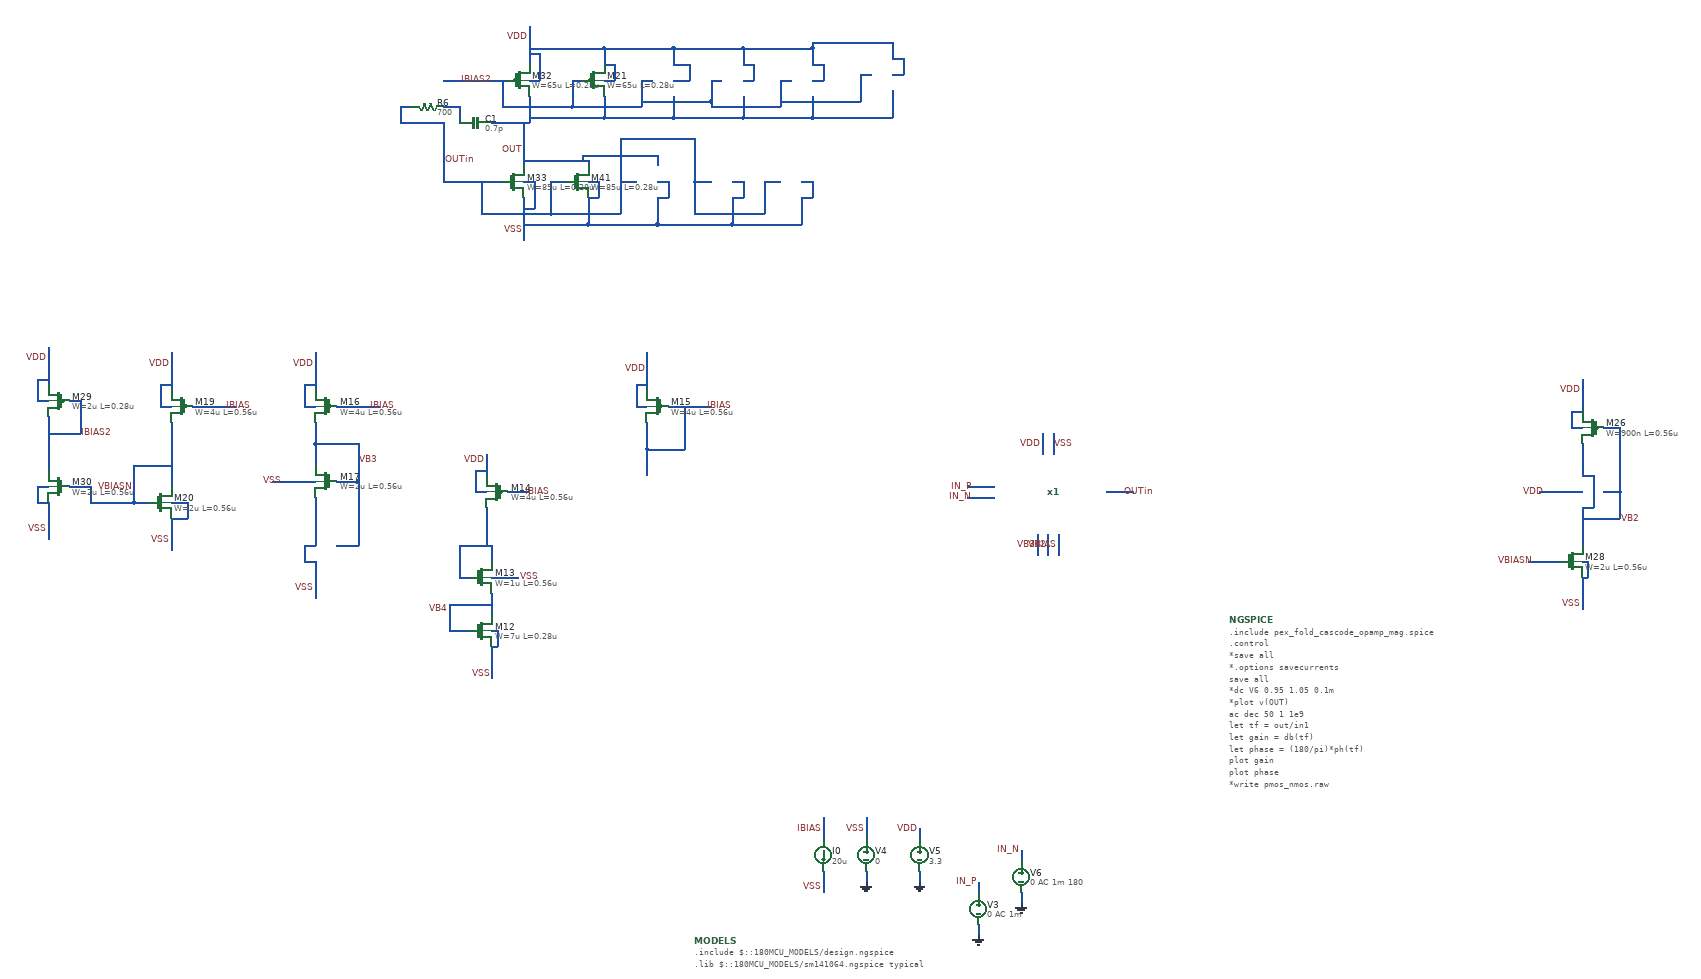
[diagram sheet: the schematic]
v {xschem version=3.1.0 file_version=1.2
}
G {}
K {}
V {}
S {}
E {}
N -460 300 -460 320 {
lab=GND}
N -460 220 -460 240 {
lab=IN_N}
N -670 200 -670 220 {
lab=GND}
N -570 200 -570 220 {
lab=GND}
N -570 120 -570 140 {
lab=VDD}
N -670 100 -670 140 {
lab=VSS}
N -380 240 -380 260 {
lab=GND}
N -380 160 -380 180 {
lab=IN_N}
N -750 200 -750 240 {
lab=VSS}
N -750 100 -750 140 {
lab=IBIAS}
N -1080 -770 -1080 -700 {
lab=VDD}
N -1100 -670 -1080 -670 {
lab=VDD}
N -1100 -710 -1100 -670 {
lab=VDD}
N -1100 -710 -1080 -710 {
lab=VDD}
N -1040 -670 -960 -670 {
lab=IBIAS}
N -1080 -640 -1080 -590 {
lab=IBIAS}
N -1080 -590 -1010 -590 {
lab=IBIAS}
N -1010 -670 -1010 -590 {
lab=IBIAS}
N -1080 -590 -1080 -540 {
lab=IBIAS}
N -1700 -770 -1700 -700 {
lab=VDD}
N -1720 -670 -1700 -670 {
lab=VDD}
N -1720 -710 -1720 -670 {
lab=VDD}
N -1720 -710 -1700 -710 {
lab=VDD}
N -1660 -670 -1580 -670 {
lab=IBIAS}
N -1700 -380 -1700 -310 {
lab=VSS}
N -1660 -410 -1620 -410 {
lab=VB3}
N -1620 -460 -1620 -410 {
lab=VB3}
N -1700 -460 -1700 -440 {
lab=VSS}
N -1700 -500 -1700 -460 {
lab=VSS}
N -1660 -530 -1620 -530 {
lab=VB3}
N -1620 -530 -1620 -460 {
lab=VB3}
N -1620 -600 -1620 -530 {
lab=VB3}
N -1700 -600 -1620 -600 {
lab=VB3}
N -1700 -640 -1700 -600 {
lab=VB3}
N -1700 -600 -1700 -560 {
lab=VB3}
N -1780 -530 -1700 -530 {
lab=VSS}
N -1720 -410 -1720 -380 {
lab=VSS}
N -1720 -380 -1700 -380 {
lab=VSS}
N -1970 -770 -1970 -700 {
lab=VDD}
N -1990 -670 -1970 -670 {
lab=VDD}
N -1990 -710 -1990 -670 {
lab=VDD}
N -1990 -710 -1970 -710 {
lab=VDD}
N -1930 -670 -1850 -670 {
lab=IBIAS}
N -1970 -640 -1970 -520 {
lab=VBIASN}
N -1970 -460 -1970 -400 {
lab=VSS}
N -1970 -490 -1940 -490 {
lab=VSS}
N -1940 -490 -1940 -460 {
lab=VSS}
N -1970 -460 -1940 -460 {
lab=VSS}
N -2040 -490 -2010 -490 {
lab=VBIASN}
N -2040 -560 -2040 -490 {
lab=VBIASN}
N -2040 -560 -1970 -560 {
lab=VBIASN}
N 670 -480 670 -410 {
lab=VB2}
N 670 -380 680 -380 {
lab=VSS}
N 680 -380 680 -350 {
lab=VSS}
N 670 -350 680 -350 {
lab=VSS}
N 670 -350 670 -290 {
lab=VSS}
N 570 -380 630 -380 {
lab=VBIASN}
N 650 -510 670 -510 {
lab=VDD}
N 670 -600 670 -540 {
lab=VB2}
N 590 -510 650 -510 {
lab=VDD}
N 670 -720 670 -660 {
lab=VDD}
N 710 -630 740 -630 {
lab=VB2}
N 670 -460 740 -460 {
lab=VB2}
N 710 -510 740 -510 {
lab=VB2}
N 650 -630 670 -630 {
lab=VDD}
N 650 -660 650 -630 {
lab=VDD}
N 650 -660 670 -660 {
lab=VDD}
N -2200 -780 -2200 -710 {
lab=VDD}
N -2220 -680 -2200 -680 {
lab=VDD}
N -2220 -720 -2220 -680 {
lab=VDD}
N -2220 -720 -2200 -720 {
lab=VDD}
N -2200 -490 -2200 -420 {
lab=VSS}
N -2220 -520 -2200 -520 {
lab=VSS}
N -2220 -520 -2220 -490 {
lab=VSS}
N -2220 -490 -2200 -490 {
lab=VSS}
N -2160 -520 -2120 -520 {
lab=VBIASN}
N -2120 -520 -2120 -490 {
lab=VBIASN}
N -2120 -490 -2040 -490 {
lab=VBIASN}
N -2200 -650 -2200 -550 {
lab=IBIAS2}
N -2160 -680 -2140 -680 {
lab=IBIAS2}
N -2140 -680 -2140 -620 {
lab=IBIAS2}
N -2200 -620 -2140 -620 {
lab=IBIAS2}
N -1300 -1380 -1300 -1310 {
lab=VDD}
N -1300 -1280 -1280 -1280 {
lab=VDD}
N -1280 -1330 -1280 -1280 {
lab=VDD}
N -1300 -1330 -1280 -1330 {
lab=VDD}
N -1460 -1280 -1340 -1280 {
lab=IBIAS2}
N -1370 -1200 -1300 -1200 {
lab=OUT}
N -1300 -1250 -1300 -1200 {
lab=OUT}
N -1310 -1200 -1310 -1120 {
lab=OUT}
N -1310 -1060 -1310 -980 {
lab=VSS}
N -1310 -1090 -1290 -1090 {
lab=VSS}
N -1290 -1090 -1290 -1040 {
lab=VSS}
N -1310 -1040 -1290 -1040 {
lab=VSS}
N -1460 -1200 -1460 -1090 {
lab=OUTin}
N -1460 -1090 -1350 -1090 {
lab=OUTin}
N -1220 -1280 -1200 -1280 {
lab=IBIAS2}
N -1220 -1280 -1220 -1230 {
lab=IBIAS2}
N -1330 -1230 -1220 -1230 {
lab=IBIAS2}
N -1350 -1230 -1330 -1230 {
lab=IBIAS2}
N -1350 -1280 -1350 -1230 {
lab=IBIAS2}
N -1160 -1340 -1160 -1310 {
lab=VDD}
N -1300 -1340 -1160 -1340 {
lab=VDD}
N -1160 -1280 -1140 -1280 {
lab=VDD}
N -1140 -1310 -1140 -1280 {
lab=VDD}
N -1160 -1310 -1140 -1310 {
lab=VDD}
N -1160 -1250 -1160 -1210 {
lab=OUT}
N -1300 -1210 -1160 -1210 {
lab=OUT}
N -1540 -1230 -1520 -1230 {
lab=OUTin}
N -1540 -1230 -1540 -1200 {
lab=OUTin}
N -1540 -1200 -1460 -1200 {
lab=OUTin}
N -1430 -1230 -1430 -1200 {
lab=#net1}
N -1460 -1230 -1430 -1230 {
lab=#net1}
N -1030 -1340 -1030 -1310 {
lab=VDD}
N -1160 -1340 -1030 -1340 {
lab=VDD}
N -1030 -1250 -1030 -1210 {
lab=OUT}
N -1160 -1210 -1030 -1210 {
lab=OUT}
N -1090 -1280 -1070 -1280 {
lab=IBIAS2}
N -1090 -1280 -1090 -1230 {
lab=IBIAS2}
N -1220 -1230 -1090 -1230 {
lab=IBIAS2}
N -1030 -1280 -1000 -1280 {
lab=VDD}
N -1000 -1310 -1000 -1280 {
lab=VDD}
N -1030 -1310 -1000 -1310 {
lab=VDD}
N -1260 -1090 -1230 -1090 {
lab=OUTin}
N -1260 -1090 -1260 -1030 {
lab=OUTin}
N -1390 -1030 -1260 -1030 {
lab=OUTin}
N -1390 -1090 -1390 -1030 {
lab=OUTin}
N -1190 -1130 -1190 -1120 {
lab=OUT}
N -1310 -1130 -1190 -1130 {
lab=OUT}
N -1190 -1060 -1190 -1010 {
lab=VSS}
N -1310 -1010 -1190 -1010 {
lab=VSS}
N -1190 -1090 -1170 -1090 {
lab=VSS}
N -1170 -1090 -1170 -1060 {
lab=VSS}
N -1190 -1060 -1170 -1060 {
lab=VSS}
N -900 -1340 -900 -1310 {
lab=VDD}
N -1030 -1340 -900 -1340 {
lab=VDD}
N -900 -1280 -880 -1280 {
lab=VDD}
N -880 -1310 -880 -1280 {
lab=VDD}
N -900 -1310 -880 -1310 {
lab=VDD}
N -960 -1280 -940 -1280 {
lab=IBIAS2}
N -960 -1280 -960 -1240 {
lab=IBIAS2}
N -1090 -1240 -960 -1240 {
lab=IBIAS2}
N -900 -1250 -900 -1210 {
lab=OUT}
N -1030 -1210 -900 -1210 {
lab=OUT}
N -1060 -1140 -1060 -1120 {
lab=OUT}
N -1200 -1140 -1060 -1140 {
lab=OUT}
N -1200 -1140 -1200 -1130 {
lab=OUT}
N -1130 -1090 -1100 -1090 {
lab=OUTin}
N -1130 -1090 -1130 -1030 {
lab=OUTin}
N -1260 -1030 -1130 -1030 {
lab=OUTin}
N -1190 -1010 -1060 -1010 {
lab=VSS}
N -1060 -1060 -1060 -1010 {
lab=VSS}
N -1060 -1090 -1040 -1090 {
lab=VSS}
N -1040 -1090 -1040 -1060 {
lab=VSS}
N -1060 -1060 -1040 -1060 {
lab=VSS}
N -770 -1340 -770 -1310 {
lab=VDD}
N -900 -1340 -770 -1340 {
lab=VDD}
N -900 -1210 -770 -1210 {
lab=OUT}
N -770 -1250 -770 -1210 {
lab=OUT}
N -770 -1280 -750 -1280 {
lab=VDD}
N -750 -1310 -750 -1280 {
lab=VDD}
N -770 -1310 -750 -1310 {
lab=VDD}
N -830 -1280 -810 -1280 {
lab=IBIAS2}
N -830 -1280 -830 -1230 {
lab=IBIAS2}
N -960 -1230 -830 -1230 {
lab=IBIAS2}
N -960 -1240 -960 -1230 {
lab=IBIAS2}
N -990 -1090 -960 -1090 {
lab=OUTin}
N -990 -1090 -990 -1030 {
lab=OUTin}
N -920 -1060 -920 -1010 {
lab=VSS}
N -920 -1090 -900 -1090 {
lab=VSS}
N -900 -1090 -900 -1060 {
lab=VSS}
N -920 -1060 -900 -1060 {
lab=VSS}
N -860 -1090 -830 -1090 {
lab=OUTin}
N -860 -1090 -860 -1030 {
lab=OUTin}
N -990 -1030 -860 -1030 {
lab=OUTin}
N -920 -1010 -790 -1010 {
lab=VSS}
N -790 -1060 -790 -1010 {
lab=VSS}
N -790 -1090 -770 -1090 {
lab=VSS}
N -770 -1090 -770 -1060 {
lab=VSS}
N -790 -1060 -770 -1060 {
lab=VSS}
N -1060 -1010 -920 -1010 {
lab=VSS}
N -990 -1170 -990 -1090 {
lab=OUTin}
N -1130 -1170 -990 -1170 {
lab=OUTin}
N -1130 -1170 -1130 -1080 {
lab=OUTin}
N -620 -1350 -620 -1320 {
lab=VDD}
N -620 -1260 -620 -1220 {
lab=OUT}
N -620 -1290 -600 -1290 {
lab=VDD}
N -600 -1320 -600 -1290 {
lab=VDD}
N -620 -1320 -600 -1320 {
lab=VDD}
N -680 -1290 -660 -1290 {
lab=IBIAS2}
N -680 -1290 -680 -1240 {
lab=IBIAS2}
N -770 -1350 -620 -1350 {
lab=VDD}
N -770 -1350 -770 -1340 {
lab=VDD}
N -620 -1220 -620 -1210 {
lab=OUT}
N -770 -1210 -620 -1210 {
lab=OUT}
N -830 -1240 -680 -1240 {
lab=IBIAS2}
N -1370 -250 -1360 -250 {
lab=VSS}
N -1360 -250 -1360 -220 {
lab=VSS}
N -1370 -220 -1360 -220 {
lab=VSS}
N -1370 -220 -1370 -160 {
lab=VSS}
N -1370 -350 -1320 -350 {
lab=VSS}
N -1370 -320 -1370 -280 {
lab=VB4}
N -1430 -350 -1410 -350 {
lab=#net2}
N -1430 -410 -1430 -350 {
lab=#net2}
N -1430 -410 -1370 -410 {
lab=#net2}
N -1370 -410 -1370 -380 {
lab=#net2}
N -1380 -480 -1380 -410 {
lab=#net2}
N -1380 -580 -1380 -540 {
lab=VDD}
N -1400 -510 -1380 -510 {
lab=VDD}
N -1400 -550 -1400 -510 {
lab=VDD}
N -1400 -550 -1380 -550 {
lab=VDD}
N -1340 -510 -1300 -510 {
lab=IBIAS}
N -1450 -300 -1370 -300 {
lab=VB4}
N -1450 -300 -1450 -250 {
lab=VB4}
N -1450 -250 -1410 -250 {
lab=VB4}
N 740 -630 740 -570 {
lab=VB2}
N 740 -510 740 -460 {
lab=VB2}
N 740 -570 740 -510 {
lab=VB2}
N 670 -480 690 -480 {
lab=VB2}
N 690 -540 690 -480 {
lab=VB2}
N 670 -540 690 -540 {
lab=VB2}
N -1720 -410 -1700 -410 {
lab=VSS}
N -1700 -440 -1700 -410 {
lab=VSS}
N -340 -620 -340 -580 {
lab=VDD}
N -320 -620 -320 -580 {
lab=VSS}
N -220 -510 -170 -510 {
lab=OUTin}
N -480 -520 -430 -520 {
lab=IN_P}
N -480 -500 -430 -500 {
lab=IN_N}
N -350 -430 -350 -390 {
lab=VB3}
N -330 -430 -330 -390 {
lab=VB2}
N -310 -430 -310 -390 {
lab=IBIAS}
C {devices/code_shown.sym} -990 330 0 0 {name=MODELS only_toplevel=true
format="tcleval( @value )"
value="
.include $::180MCU_MODELS/design.ngspice
.lib $::180MCU_MODELS/sm141064.ngspice typical
"}
C {devices/code_shown.sym} 10 -270 0 0 {name=NGSPICE only_toplevel=true
value="
.include "pex_fold_cascode_opamp_mag.spice"
.control
*save all
*.options savecurrents
save all 


*dc V6 0.95 1.05 0.1m
*plot v(OUT)

ac dec 50 1 1e9
let tf = out/in1
let gain = db(tf)
let phase = (180/pi)*ph(tf)

plot gain
plot phase

*write pmos_nmos.raw
*let vdiff = @m.xm1.m0[vdsat]+vds
*plot @m.xm1.m0[vdsat]
*tran 1u 2m
*let gain = (maximum(out1)-minimum(out2) )* 1000
*print vbb


*plot vdiff
display all
.endc
"}
C {devices/vsource.sym} -460 270 0 0 {name=V3 value="0 AC 1m"}
C {devices/gnd.sym} -460 320 0 0 {name=l1 lab=GND}
C {devices/lab_pin.sym} -460 220 0 0 {name=p12 sig_type=std_logic lab=IN_P}
C {devices/vsource.sym} -670 170 0 0 {name=V4 value=0}
C {devices/gnd.sym} -670 220 0 0 {name=l4 lab=GND}
C {devices/vsource.sym} -570 170 0 0 {name=V5 value=3.3}
C {devices/gnd.sym} -570 220 0 0 {name=l5 lab=GND}
C {devices/lab_wire.sym} -570 120 0 0 {name=p14 sig_type=std_logic lab=VDD}
C {devices/lab_wire.sym} -670 120 0 0 {name=p15 sig_type=std_logic lab=VSS}
C {devices/vsource.sym} -380 210 0 0 {name=V6 value="0 AC 1m 180"}
C {devices/gnd.sym} -380 260 0 0 {name=l6 lab=GND}
C {devices/lab_pin.sym} -380 160 0 0 {name=p16 sig_type=std_logic lab=IN_N}
C {devices/isource.sym} -750 170 0 0 {name=I0 value=20u}
C {devices/lab_wire.sym} -750 230 0 0 {name=p3 sig_type=std_logic lab=VSS}
C {devices/lab_wire.sym} -750 120 0 0 {name=p4 sig_type=std_logic lab=IBIAS}
C {symbols/pfet_03v3.sym} -1060 -670 0 1 {name=M15
L=0.56u
W=4u
nf=1
m=1
ad="'int((nf+1)/2) * W/nf * 0.18u'"
pd="'2*int((nf+1)/2) * (W/nf + 0.18u)'"
as="'int((nf+2)/2) * W/nf * 0.18u'"
ps="'2*int((nf+2)/2) * (W/nf + 0.18u)'"
nrd="'0.18u / W'" nrs="'0.18u / W'"
sa=0 sb=0 sd=0
model=pfet_03v3
spiceprefix=X
}
C {devices/lab_wire.sym} -1080 -740 0 0 {name=p10 sig_type=std_logic lab=VDD}
C {devices/lab_wire.sym} -970 -670 0 1 {name=p1 sig_type=std_logic lab=IBIAS}
C {symbols/pfet_03v3.sym} -1680 -670 0 1 {name=M16
L=0.56u
W=4u
nf=1
m=1
ad="'int((nf+1)/2) * W/nf * 0.18u'"
pd="'2*int((nf+1)/2) * (W/nf + 0.18u)'"
as="'int((nf+2)/2) * W/nf * 0.18u'"
ps="'2*int((nf+2)/2) * (W/nf + 0.18u)'"
nrd="'0.18u / W'" nrs="'0.18u / W'"
sa=0 sb=0 sd=0
model=pfet_03v3
spiceprefix=X
}
C {devices/lab_wire.sym} -1700 -750 0 0 {name=p24 sig_type=std_logic lab=VDD}
C {devices/lab_wire.sym} -1600 -670 0 1 {name=p25 sig_type=std_logic lab=IBIAS}
C {symbols/nfet_03v3.sym} -1680 -530 0 1 {name=M17
L=0.56u
W=2u
nf=1
m=1
ad="'int((nf+1)/2) * W/nf * 0.18u'"
pd="'2*int((nf+1)/2) * (W/nf + 0.18u)'"
as="'int((nf+2)/2) * W/nf * 0.18u'"
ps="'2*int((nf+2)/2) * (W/nf + 0.18u)'"
nrd="'0.18u / W'" nrs="'0.18u / W'"
sa=0 sb=0 sd=0
model=nfet_03v3
spiceprefix=X
}
C {devices/lab_wire.sym} -1760 -530 0 0 {name=p26 sig_type=std_logic lab=VSS}
C {devices/lab_wire.sym} -1620 -570 0 1 {name=p27 sig_type=std_logic lab=VB3}
C {symbols/pfet_03v3.sym} -1950 -670 0 1 {name=M19
L=0.56u
W=4u
nf=1
m=1
ad="'int((nf+1)/2) * W/nf * 0.18u'"
pd="'2*int((nf+1)/2) * (W/nf + 0.18u)'"
as="'int((nf+2)/2) * W/nf * 0.18u'"
ps="'2*int((nf+2)/2) * (W/nf + 0.18u)'"
nrd="'0.18u / W'" nrs="'0.18u / W'"
sa=0 sb=0 sd=0
model=pfet_03v3
spiceprefix=X
}
C {devices/lab_wire.sym} -1970 -750 0 0 {name=p28 sig_type=std_logic lab=VDD}
C {devices/lab_wire.sym} -1870 -670 0 1 {name=p29 sig_type=std_logic lab=IBIAS}
C {symbols/nfet_03v3.sym} -1990 -490 0 0 {name=M20
L=0.56u
W=2u
nf=1
m=1
ad="'int((nf+1)/2) * W/nf * 0.18u'"
pd="'2*int((nf+1)/2) * (W/nf + 0.18u)'"
as="'int((nf+2)/2) * W/nf * 0.18u'"
ps="'2*int((nf+2)/2) * (W/nf + 0.18u)'"
nrd="'0.18u / W'" nrs="'0.18u / W'"
sa=0 sb=0 sd=0
model=nfet_03v3
spiceprefix=X
}
C {devices/lab_wire.sym} -2040 -520 0 0 {name=p30 sig_type=std_logic lab=VBIASN}
C {symbols/pfet_03v3.sym} 690 -630 0 1 {name=M26
L=0.56u
W=900n
nf=1
m=1
ad="'int((nf+1)/2) * W/nf * 0.18u'"
pd="'2*int((nf+1)/2) * (W/nf + 0.18u)'"
as="'int((nf+2)/2) * W/nf * 0.18u'"
ps="'2*int((nf+2)/2) * (W/nf + 0.18u)'"
nrd="'0.18u / W'" nrs="'0.18u / W'"
sa=0 sb=0 sd=0
model=pfet_03v3
spiceprefix=X
}
C {symbols/nfet_03v3.sym} 650 -380 0 0 {name=M28
L=0.56u
W=2u
nf=1
m=1
ad="'int((nf+1)/2) * W/nf * 0.18u'"
pd="'2*int((nf+1)/2) * (W/nf + 0.18u)'"
as="'int((nf+2)/2) * W/nf * 0.18u'"
ps="'2*int((nf+2)/2) * (W/nf + 0.18u)'"
nrd="'0.18u / W'" nrs="'0.18u / W'"
sa=0 sb=0 sd=0
model=nfet_03v3
spiceprefix=X
}
C {devices/lab_wire.sym} 670 -700 0 0 {name=p39 sig_type=std_logic lab=VDD}
C {devices/lab_wire.sym} 600 -510 0 0 {name=p40 sig_type=std_logic lab=VDD}
C {devices/lab_wire.sym} 670 -300 0 0 {name=p41 sig_type=std_logic lab=VSS}
C {devices/lab_wire.sym} 580 -380 0 0 {name=p42 sig_type=std_logic lab=VBIASN}
C {devices/lab_wire.sym} 740 -460 0 1 {name=p43 sig_type=std_logic lab=VB2}
C {devices/lab_wire.sym} -1700 -330 0 0 {name=p48 sig_type=std_logic lab=VSS}
C {devices/lab_wire.sym} -1970 -420 0 0 {name=p52 sig_type=std_logic lab=VSS}
C {symbols/pfet_03v3.sym} -2180 -680 0 1 {name=M29
L=0.28u
W=2u
nf=1
m=1
ad="'int((nf+1)/2) * W/nf * 0.18u'"
pd="'2*int((nf+1)/2) * (W/nf + 0.18u)'"
as="'int((nf+2)/2) * W/nf * 0.18u'"
ps="'2*int((nf+2)/2) * (W/nf + 0.18u)'"
nrd="'0.18u / W'" nrs="'0.18u / W'"
sa=0 sb=0 sd=0
model=pfet_03v3
spiceprefix=X
}
C {devices/lab_wire.sym} -2200 -760 0 0 {name=p53 sig_type=std_logic lab=VDD}
C {symbols/nfet_03v3.sym} -2180 -520 0 1 {name=M30
L=0.56u
W=2u
nf=1
m=1
ad="'int((nf+1)/2) * W/nf * 0.18u'"
pd="'2*int((nf+1)/2) * (W/nf + 0.18u)'"
as="'int((nf+2)/2) * W/nf * 0.18u'"
ps="'2*int((nf+2)/2) * (W/nf + 0.18u)'"
nrd="'0.18u / W'" nrs="'0.18u / W'"
sa=0 sb=0 sd=0
model=nfet_03v3
spiceprefix=X
}
C {devices/lab_wire.sym} -2140 -620 0 1 {name=p54 sig_type=std_logic lab=IBIAS2}
C {symbols/pfet_03v3.sym} -1320 -1280 0 0 {name=M32
L=0.28u
W=65u
nf=1
m=1
ad="'int((nf+1)/2) * W/nf * 0.18u'"
pd="'2*int((nf+1)/2) * (W/nf + 0.18u)'"
as="'int((nf+2)/2) * W/nf * 0.18u'"
ps="'2*int((nf+2)/2) * (W/nf + 0.18u)'"
nrd="'0.18u / W'" nrs="'0.18u / W'"
sa=0 sb=0 sd=0
model=pfet_03v3
spiceprefix=X
}
C {symbols/nfet_03v3.sym} -1330 -1090 0 0 {name=M33
L=0.28u
W=85u
nf=1
m=1
ad="'int((nf+1)/2) * W/nf * 0.18u'"
pd="'2*int((nf+1)/2) * (W/nf + 0.18u)'"
as="'int((nf+2)/2) * W/nf * 0.18u'"
ps="'2*int((nf+2)/2) * (W/nf + 0.18u)'"
nrd="'0.18u / W'" nrs="'0.18u / W'"
sa=0 sb=0 sd=0
model=nfet_03v3
spiceprefix=X
}
C {devices/lab_wire.sym} -1300 -1360 0 0 {name=p55 sig_type=std_logic lab=VDD}
C {devices/lab_wire.sym} -1310 -1000 0 0 {name=p56 sig_type=std_logic lab=VSS}
C {devices/res.sym} -1490 -1230 1 0 {name=R6
value=700
footprint=1206
device=resistor
m=1}
C {symbols/nfet_03v3.sym} -1210 -1090 0 0 {name=M41
L=0.28u
W=85u
nf=1
m=1
ad="'int((nf+1)/2) * W/nf * 0.18u'"
pd="'2*int((nf+1)/2) * (W/nf + 0.18u)'"
as="'int((nf+2)/2) * W/nf * 0.18u'"
ps="'2*int((nf+2)/2) * (W/nf + 0.18u)'"
nrd="'0.18u / W'" nrs="'0.18u / W'"
sa=0 sb=0 sd=0
model=nfet_03v3
spiceprefix=X
}
C {devices/lab_wire.sym} -1310 -1150 0 0 {name=p62 sig_type=std_logic lab=OUT
}
C {devices/lab_wire.sym} -1430 -1280 0 1 {name=p64 sig_type=std_logic lab=IBIAS2}
C {devices/lab_wire.sym} -1460 -1130 0 1 {name=p60 sig_type=std_logic lab=OUTin}
C {devices/lab_wire.sym} -2200 -440 0 0 {name=p67 sig_type=std_logic lab=VSS}
C {symbols/nfet_03v3.sym} -1390 -250 0 0 {name=M12
L=0.28u
W=7u
nf=1
m=1
ad="'int((nf+1)/2) * W/nf * 0.18u'"
pd="'2*int((nf+1)/2) * (W/nf + 0.18u)'"
as="'int((nf+2)/2) * W/nf * 0.18u'"
ps="'2*int((nf+2)/2) * (W/nf + 0.18u)'"
nrd="'0.18u / W'" nrs="'0.18u / W'"
sa=0 sb=0 sd=0
model=nfet_03v3
spiceprefix=X
}
C {devices/lab_wire.sym} -1370 -170 0 0 {name=p9 sig_type=std_logic lab=VSS}
C {symbols/nfet_03v3.sym} -1390 -350 0 0 {name=M13
L=0.56u
W=1u
nf=1
m=1
ad="'int((nf+1)/2) * W/nf * 0.18u'"
pd="'2*int((nf+1)/2) * (W/nf + 0.18u)'"
as="'int((nf+2)/2) * W/nf * 0.18u'"
ps="'2*int((nf+2)/2) * (W/nf + 0.18u)'"
nrd="'0.18u / W'" nrs="'0.18u / W'"
sa=0 sb=0 sd=0
model=nfet_03v3
spiceprefix=X
}
C {symbols/pfet_03v3.sym} -1360 -510 0 1 {name=M14
L=0.56u
W=4u
nf=1
m=1
ad="'int((nf+1)/2) * W/nf * 0.18u'"
pd="'2*int((nf+1)/2) * (W/nf + 0.18u)'"
as="'int((nf+2)/2) * W/nf * 0.18u'"
ps="'2*int((nf+2)/2) * (W/nf + 0.18u)'"
nrd="'0.18u / W'" nrs="'0.18u / W'"
sa=0 sb=0 sd=0
model=pfet_03v3
spiceprefix=X
}
C {devices/lab_wire.sym} -1380 -570 0 0 {name=p13 sig_type=std_logic lab=VDD}
C {devices/lab_wire.sym} -1320 -350 0 1 {name=p2 sig_type=std_logic lab=VSS}
C {devices/lab_wire.sym} -1310 -510 0 1 {name=p5 sig_type=std_logic lab=IBIAS}
C {devices/lab_wire.sym} -1450 -290 0 0 {name=p11 sig_type=std_logic lab=VB4}
C {symbols/pfet_03v3.sym} -1180 -1280 0 0 {name=M21
L=0.28u
W=65u
nf=1
m=1
ad="'int((nf+1)/2) * W/nf * 0.18u'"
pd="'2*int((nf+1)/2) * (W/nf + 0.18u)'"
as="'int((nf+2)/2) * W/nf * 0.18u'"
ps="'2*int((nf+2)/2) * (W/nf + 0.18u)'"
nrd="'0.18u / W'" nrs="'0.18u / W'"
sa=0 sb=0 sd=0
model=pfet_03v3
spiceprefix=X
}
C {devices/capa.sym} -1400 -1200 3 0 {name=C1
m=1
value=0.7p
footprint=1206
device="ceramic capacitor"}
C {devices/lab_wire.sym} -340 -600 0 0 {name=p31 sig_type=std_logic lab=VDD}
C {devices/lab_wire.sym} -320 -600 0 1 {name=p32 sig_type=std_logic lab=VSS}
C {devices/lab_wire.sym} -350 -410 3 0 {name=p33 sig_type=std_logic lab=VB3}
C {devices/lab_wire.sym} -330 -410 3 0 {name=p34 sig_type=std_logic lab=VB2}
C {devices/lab_wire.sym} -310 -410 1 1 {name=p36 sig_type=std_logic lab=IBIAS}
C {devices/lab_wire.sym} -190 -510 0 1 {name=p37 sig_type=std_logic lab=OUTin}
C {devices/lab_wire.sym} -470 -500 0 0 {name=p38 sig_type=std_logic lab=IN_N}
C {devices/lab_wire.sym} -470 -520 0 0 {name=p44 sig_type=std_logic lab=IN_P}
C {pex_fold_cascode_opamp_mag.sym} -330 -510 0 0 {name=x1}
